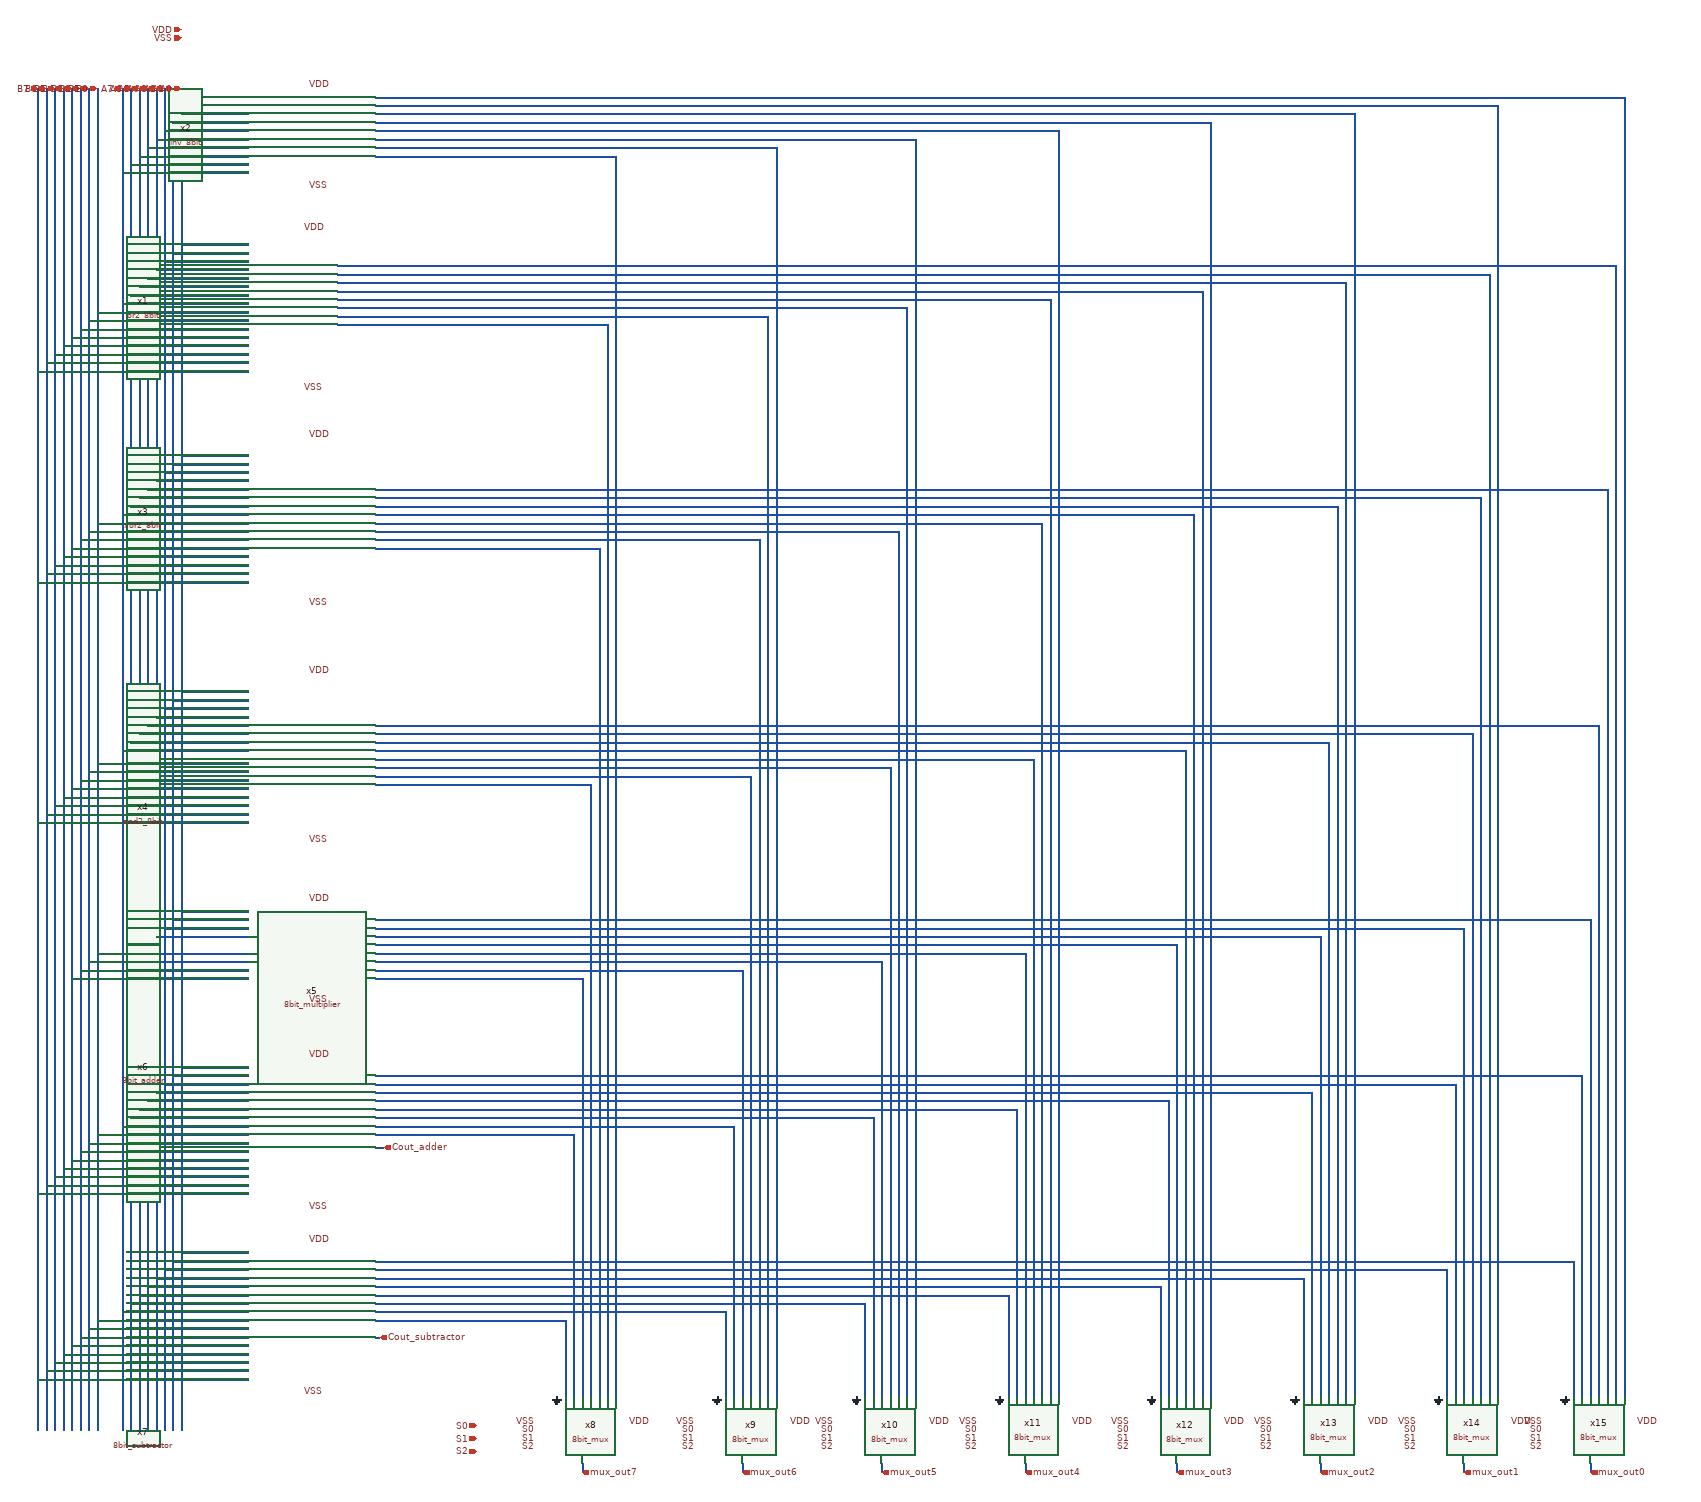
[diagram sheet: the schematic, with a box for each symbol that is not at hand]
v {xschem version=3.1.0 file_version=1.2 }
G {}
K {}
V {}
S {}
E {}
N -1880 -1640 -1880 1540 {
lab=A0}
N -1900 -1640 -1900 1540 {
lab=A1}
N -1920 -1640 -1920 1540 {
lab=A2}
N -1940 -1640 -1940 1540 {
lab=A3}
N -1960 -1640 -1960 1540 {
lab=A4}
N -1980 -1640 -1980 1540 {
lab=A5}
N -2000 -1640 -2000 1540 {
lab=A6}
N -2020 -1640 -2020 1540 {
lab=A7}
N -2080 -1640 -2080 1540 {
lab=B0}
N -2100 -1640 -2100 1540 {
lab=B1}
N -2120 -1640 -2120 1540 {
lab=B2}
N -2140 -1640 -2140 1540 {
lab=B3}
N -2160 -1640 -2160 1540 {
lab=B4}
N -2180 -1640 -2180 1540 {
lab=B5}
N -2200 -1640 -2200 1540 {
lab=B6}
N -2220 -1640 -2220 1540 {
lab=B7}
N -1880 -1580 -1720 -1580 {
lab=A0}
N -1900 -1560 -1720 -1560 {
lab=A1}
N -1920 -1540 -1720 -1540 {
lab=A2}
N -1940 -1520 -1720 -1520 {
lab=A3}
N -1960 -1500 -1720 -1500 {
lab=A4}
N -2000 -1460 -1720 -1460 {
lab=A6}
N -1980 -1480 -1720 -1480 {
lab=A5}
N -2020 -1440 -1720 -1440 {
lab=A7}
N -1880 -1270 -1720 -1270 {
lab=A0}
N -1900 -1250 -1720 -1250 {
lab=A1}
N -1920 -1230 -1720 -1230 {
lab=A2}
N -1940 -1210 -1720 -1210 {
lab=A3}
N -1960 -1190 -1720 -1190 {
lab=A4}
N -1980 -1170 -1720 -1170 {
lab=A5}
N -2000 -1150 -1720 -1150 {
lab=A6}
N -2020 -1130 -1720 -1130 {
lab=A7}
N -2080 -1110 -1720 -1110 {
lab=B0}
N -2100 -1090 -1720 -1090 {
lab=B1}
N -2120 -1070 -1720 -1070 {
lab=B2}
N -2140 -1050 -1720 -1050 {
lab=B3}
N -2160 -1030 -1720 -1030 {
lab=B4}
N -2180 -1010 -1720 -1010 {
lab=B5}
N -2200 -990 -1720 -990 {
lab=B6}
N -2220 -970 -1720 -970 {
lab=B7}
N -1880 -770 -1720 -770 {
lab=A0}
N -1900 -750 -1720 -750 {
lab=A1}
N -1920 -730 -1720 -730 {
lab=A2}
N -1940 -710 -1720 -710 {
lab=A3}
N -1960 -690 -1720 -690 {
lab=A4}
N -1980 -670 -1720 -670 {
lab=A5}
N -2000 -650 -1720 -650 {
lab=A6}
N -2020 -630 -1720 -630 {
lab=A7}
N -2080 -610 -1720 -610 {
lab=B0}
N -2100 -590 -1720 -590 {
lab=B1}
N -2120 -570 -1720 -570 {
lab=B2}
N -2140 -550 -1720 -550 {
lab=B3}
N -2160 -530 -1720 -530 {
lab=B4}
N -2180 -510 -1720 -510 {
lab=B5}
N -2200 -490 -1720 -490 {
lab=B6}
N -2220 -470 -1720 -470 {
lab=B7}
N -1880 -210 -1720 -210 {
lab=A0}
N -1900 -190 -1720 -190 {
lab=A1}
N -1920 -170 -1720 -170 {
lab=A2}
N -1940 -150 -1720 -150 {
lab=A3}
N -1950 -130 -1720 -130 {
lab=A4}
N -1960 -130 -1950 -130 {
lab=A4}
N -1980 -110 -1720 -110 {
lab=A5}
N -2000 -90 -1720 -90 {
lab=A6}
N -2020 -70 -1720 -70 {
lab=A7}
N -2080 -40 -1720 -40 {
lab=B0}
N -2100 -20 -1720 -20 {
lab=B1}
N -2120 0 -1720 0 {
lab=B2}
N -2140 20 -1720 20 {
lab=B3}
N -2160 40 -1720 40 {
lab=B4}
N -2180 60 -1720 60 {
lab=B5}
N -2200 80 -1720 80 {
lab=B6}
N -2220 100 -1720 100 {
lab=B7}
N -1880 310 -1720 310 {
lab=A0}
N -1900 330 -1720 330 {
lab=A1}
N -1920 350 -1720 350 {
lab=A2}
N -1940 370 -1720 370 {
lab=A3}
N -2080 410 -1720 410 {
lab=B0}
N -2100 430 -1720 430 {
lab=B1}
N -2120 450 -1720 450 {
lab=B2}
N -2140 470 -1720 470 {
lab=B3}
N -1880 680 -1720 680 {
lab=A0}
N -1900 700 -1720 700 {
lab=A1}
N -1920 720 -1720 720 {
lab=A2}
N -1940 740 -1720 740 {
lab=A3}
N -1960 760 -1720 760 {
lab=A4}
N -1980 780 -1720 780 {
lab=A5}
N -2000 800 -1720 800 {
lab=A6}
N -2020 820 -1720 820 {
lab=A7}
N -2080 840 -1720 840 {
lab=B0}
N -2100 860 -1720 860 {
lab=B1}
N -2120 880 -1720 880 {
lab=B2}
N -2140 900 -1720 900 {
lab=B3}
N -2160 920 -1720 920 {
lab=B4}
N -2180 940 -1720 940 {
lab=B5}
N -2200 960 -1720 960 {
lab=B6}
N -2220 980 -1720 980 {
lab=B7}
N -1880 1120 -1720 1120 {
lab=A0}
N -1900 1140 -1720 1140 {
lab=A1}
N -1920 1160 -1720 1160 {
lab=A2}
N -1940 1180 -1720 1180 {
lab=A3}
N -1960 1200 -1720 1200 {
lab=A4}
N -1980 1220 -1720 1220 {
lab=A5}
N -2000 1240 -1720 1240 {
lab=A6}
N -2020 1260 -1720 1260 {
lab=A7}
N -2080 1280 -1720 1280 {
lab=B0}
N -2100 1300 -1720 1300 {
lab=B1}
N -2120 1320 -1720 1320 {
lab=B2}
N -2140 1340 -1720 1340 {
lab=B3}
N -2160 1360 -1720 1360 {
lab=B4}
N -2180 1380 -1720 1380 {
lab=B5}
N -2200 1400 -1720 1400 {
lab=B6}
N -2220 1420 -1720 1420 {
lab=B7}
N -1420 -1480 -1140 -1480 {
lab=#net1}
N -1140 -1480 -1090 -1480 {
lab=#net1}
N -1090 -1480 -1040 -1480 {
lab=#net1}
N -850 -1470 -850 1470 {
lab=#net1}
N -1040 -1480 -970 -1480 {
lab=#net1}
N -470 -1470 -470 1470 {
lab=#net2}
N -140 -1470 -140 1470 {
lab=#net3}
N 200 -1480 200 1460 {
lab=#net4}
N 560 -1470 560 1470 {
lab=#net5}
N 900 -1480 900 1460 {
lab=#net6}
N 1240 -1480 1240 1460 {
lab=#net7}
N 1540 -1480 1540 1460 {
lab=#net8}
N -1420 -1500 -590 -1500 {
lab=#net2}
N -1420 -1520 -260 -1520 {
lab=#net3}
N -1420 -1540 80 -1540 {
lab=#net4}
N -1420 -1560 440 -1560 {
lab=#net5}
N -1420 -1580 780 -1580 {
lab=#net6}
N -1420 -1600 1120 -1600 {
lab=#net7}
N -1420 -1620 1420 -1620 {
lab=#net8}
N -970 -1480 -850 -1480 {
lab=#net1}
N -850 -1480 -850 -1470 {
lab=#net1}
N -590 -1500 -470 -1500 {
lab=#net2}
N -470 -1500 -470 -1470 {
lab=#net2}
N -260 -1520 -140 -1520 {
lab=#net3}
N -140 -1520 -140 -1470 {
lab=#net3}
N 80 -1540 200 -1540 {
lab=#net4}
N 200 -1540 200 -1480 {
lab=#net4}
N 440 -1560 560 -1560 {
lab=#net5}
N 560 -1560 560 -1470 {
lab=#net5}
N 780 -1580 900 -1580 {
lab=#net6}
N 900 -1580 900 -1480 {
lab=#net6}
N 1120 -1600 1240 -1600 {
lab=#net7}
N 1240 -1600 1240 -1480 {
lab=#net7}
N 1420 -1620 1540 -1620 {
lab=#net8}
N 1540 -1620 1540 -1480 {
lab=#net8}
N -870 -1080 -870 1460 {
lab=#net9}
N -1510 -1080 -870 -1080 {
lab=#net9}
N -490 -1080 -490 1460 {
lab=#net10}
N -160 -1080 -160 1460 {
lab=#net11}
N 180 -1080 180 1460 {
lab=#net12}
N 540 -1080 540 1460 {
lab=#net13}
N 880 -1080 880 1460 {
lab=#net14}
N 1220 -1080 1220 1460 {
lab=#net15}
N 1520 -1080 1520 1460 {
lab=#net16}
N -1510 -1100 -490 -1100 {
lab=#net10}
N -490 -1100 -490 -1080 {
lab=#net10}
N -1510 -1120 -160 -1120 {
lab=#net11}
N -160 -1120 -160 -1080 {
lab=#net11}
N -1510 -1140 180 -1140 {
lab=#net12}
N 180 -1140 180 -1080 {
lab=#net12}
N -1510 -1160 540 -1160 {
lab=#net13}
N 540 -1160 540 -1080 {
lab=#net13}
N -1510 -1180 880 -1180 {
lab=#net14}
N 880 -1180 880 -1080 {
lab=#net14}
N -1510 -1200 1220 -1200 {
lab=#net15}
N 1220 -1200 1220 -1080 {
lab=#net15}
N -1510 -1220 1520 -1220 {
lab=#net16}
N 1520 -1220 1520 -1080 {
lab=#net16}
N -890 -550 -890 1460 {
lab=#net17}
N -1420 -550 -890 -550 {
lab=#net17}
N -510 -550 -510 1460 {
lab=#net18}
N -180 -550 -180 1460 {
lab=#net19}
N 160 -550 160 1460 {
lab=#net20}
N 520 -550 520 1460 {
lab=#net21}
N 860 -550 860 1460 {
lab=#net22}
N 1200 -550 1200 1460 {
lab=#net23}
N 1500 -550 1500 1460 {
lab=#net24}
N -1420 -570 -510 -570 {
lab=#net18}
N -510 -570 -510 -550 {
lab=#net18}
N -1420 -590 -180 -590 {
lab=#net19}
N -180 -590 -180 -550 {
lab=#net19}
N -1420 -610 160 -610 {
lab=#net20}
N 160 -610 160 -550 {
lab=#net20}
N -1420 -630 520 -630 {
lab=#net21}
N 520 -630 520 -550 {
lab=#net21}
N -1420 -650 860 -650 {
lab=#net22}
N 860 -650 860 -550 {
lab=#net22}
N -1420 -670 1200 -670 {
lab=#net23}
N 1200 -670 1200 -550 {
lab=#net23}
N -1420 -690 1490 -690 {
lab=#net24}
N 1490 -690 1500 -690 {
lab=#net24}
N 1500 -690 1500 -550 {
lab=#net24}
N -910 10 -910 1460 {
lab=#net25}
N -1420 10 -910 10 {
lab=#net25}
N -530 10 -530 1460 {
lab=#net26}
N -200 10 -200 1460 {
lab=#net27}
N 140 10 140 1460 {
lab=#net28}
N 500 10 500 1460 {
lab=#net29}
N 840 10 840 1460 {
lab=#net30}
N 1180 10 1180 1460 {
lab=#net31}
N 1480 10 1480 1460 {
lab=#net32}
N -1420 -10 -530 -10 {
lab=#net26}
N -530 -10 -530 10 {
lab=#net26}
N -1420 -30 -200 -30 {
lab=#net27}
N -200 -30 -200 10 {
lab=#net27}
N -1420 -50 140 -50 {
lab=#net28}
N 140 -50 140 10 {
lab=#net28}
N -1420 -70 500 -70 {
lab=#net29}
N 500 -70 500 10 {
lab=#net29}
N -1420 -90 840 -90 {
lab=#net30}
N 840 -90 840 10 {
lab=#net30}
N -1420 -110 1180 -110 {
lab=#net31}
N 1180 -110 1180 10 {
lab=#net31}
N -1420 -130 1480 -130 {
lab=#net32}
N 1480 -130 1480 10 {
lab=#net32}
N -930 470 -930 1460 {
lab=#net33}
N -1420 470 -930 470 {
lab=#net33}
N -550 470 -550 1460 {
lab=#net34}
N -220 470 -220 1460 {
lab=#net35}
N 120 470 120 1460 {
lab=#net36}
N 480 470 480 1460 {
lab=#net37}
N 820 470 820 1460 {
lab=#net38}
N 1160 470 1160 1460 {
lab=#net39}
N 1460 470 1460 1460 {
lab=#net40}
N -1420 450 -550 450 {
lab=#net34}
N -550 450 -550 470 {
lab=#net34}
N -1420 430 -220 430 {
lab=#net35}
N -220 430 -220 470 {
lab=#net35}
N -1420 410 120 410 {
lab=#net36}
N 120 410 120 470 {
lab=#net36}
N -1420 390 480 390 {
lab=#net37}
N 480 390 480 470 {
lab=#net37}
N -1420 370 820 370 {
lab=#net38}
N 820 370 820 470 {
lab=#net38}
N -1420 350 1160 350 {
lab=#net39}
N 1160 350 1160 470 {
lab=#net39}
N -1420 330 1460 330 {
lab=#net40}
N 1460 330 1460 470 {
lab=#net40}
N -950 840 -950 1460 {
lab=#net41}
N -1420 840 -950 840 {
lab=#net41}
N -1420 820 -570 820 {
lab=#net42}
N -570 820 -570 1460 {
lab=#net42}
N -1420 800 -240 800 {
lab=#net43}
N -240 800 -240 1460 {
lab=#net43}
N -1420 780 100 780 {
lab=#net44}
N 100 780 100 1460 {
lab=#net44}
N -1420 760 460 760 {
lab=#net45}
N 460 760 460 1460 {
lab=#net45}
N -1420 740 800 740 {
lab=#net46}
N 800 740 800 1460 {
lab=#net46}
N -1420 720 1140 720 {
lab=#net47}
N 1140 720 1140 1460 {
lab=#net47}
N -1420 700 1440 700 {
lab=#net48}
N 1440 700 1440 1460 {
lab=#net48}
N -1420 1280 -970 1280 {
lab=#net49}
N -970 1280 -970 1460 {
lab=#net49}
N -1420 1260 -590 1260 {
lab=#net50}
N -590 1260 -590 1460 {
lab=#net50}
N -1420 1240 -260 1240 {
lab=#net51}
N -260 1240 -260 1460 {
lab=#net51}
N 780 1200 780 1460 {
lab=#net52}
N 1120 1180 1120 1460 {
lab=#net53}
N 1420 1160 1420 1460 {
lab=#net54}
N -1420 1220 80 1220 {
lab=#net55}
N 80 1220 80 1460 {
lab=#net55}
N -1420 1200 440 1200 {
lab=#net56}
N 440 1200 440 1460 {
lab=#net56}
N -1420 1180 780 1180 {
lab=#net52}
N 780 1180 780 1200 {
lab=#net52}
N -1420 1160 1120 1160 {
lab=#net53}
N 1120 1160 1120 1180 {
lab=#net53}
N -1420 1140 1420 1140 {
lab=#net54}
N 1420 1140 1420 1160 {
lab=#net54}
N -1420 1320 -1410 1320 {
lab=Cout_subtractor}
N -1420 870 -1400 870 {
lab=Cout_adder}
N -930 1620 -930 1640 {
lab=mux_out7}
N -550 1620 -550 1640 {
lab=mux_out6}
N -220 1620 -220 1640 {
lab=mux_out5}
N 120 1620 120 1640 {
lab=mux_out4}
N 480 1620 480 1640 {
lab=mux_out3}
N 820 1620 820 1640 {
lab=mux_out2}
N 1160 1620 1160 1640 {
lab=mux_out1}
N 1460 1620 1460 1640 {
lab=mux_out0}
C {or/or2_8bit.sym} -1570 -1140 0 0 {name=x1}
C {inv/inv_8bit.sym} -1570 -1530 0 0 {name=x2}
C {xor2/xor2_8bit.sym} -1570 -620 0 0 {name=x3}
C {and/and2_8bit.sym} -1570 -60 0 0 {name=x4}
C {8bit_multiplier.sym} -1320 540 0 0 {name=x5}
C {8bit_adder.sym} -1570 830 0 0 {name=x6}
C {8bit_subtractor.sym} -1570 1270 0 0 {name=x7}
C {devices/ipin.sym} -1900 -1640 1 0 {name=p2 lab=A1}
C {devices/ipin.sym} -1920 -1640 1 0 {name=p3 lab=A2}
C {devices/ipin.sym} -1940 -1640 1 0 {name=p4 lab=A3}
C {devices/ipin.sym} -1960 -1640 1 0 {name=p5 lab=A4}
C {devices/ipin.sym} -1980 -1640 1 0 {name=p6 lab=A5}
C {devices/ipin.sym} -2000 -1640 1 0 {name=p7 lab=A6}
C {devices/ipin.sym} -2020 -1640 1 0 {name=p8 lab=A7}
C {devices/ipin.sym} -1880 -1640 1 0 {name=p9 lab=A0}
C {devices/ipin.sym} -2100 -1640 1 0 {name=p11 lab=B1}
C {devices/ipin.sym} -2120 -1640 1 0 {name=p12 lab=B2}
C {devices/ipin.sym} -2140 -1640 1 0 {name=p13 lab=B3}
C {devices/ipin.sym} -2160 -1640 1 0 {name=p14 lab=B4}
C {devices/ipin.sym} -2180 -1640 1 0 {name=p15 lab=B5}
C {devices/ipin.sym} -2200 -1640 1 0 {name=p16 lab=B6}
C {devices/ipin.sym} -2220 -1640 1 0 {name=p17 lab=B7}
C {devices/ipin.sym} -2080 -1640 1 0 {name=p18 lab=B0}
C {devices/ipin.sym} -1880 -1780 0 0 {name=p1 lab=VDD}
C {devices/ipin.sym} -1880 -1760 0 0 {name=p10 lab=VSS}
C {devices/lab_pin.sym} -1580 -1650 2 0 {name=l1 sig_type=std_logic lab=VDD}
C {devices/lab_pin.sym} -1580 -1410 2 0 {name=l2 sig_type=std_logic lab=VSS}
C {8bit_mux.sym} -940 1600 1 0 {name=x8}
C {8bit_mux.sym} -560 1600 1 0 {name=x9}
C {8bit_mux.sym} -230 1600 1 0 {name=x10}
C {8bit_mux.sym} 110 1600 1 0 {name=x11}
C {8bit_mux.sym} 470 1600 1 0 {name=x12}
C {8bit_mux.sym} 810 1600 1 0 {name=x13}
C {8bit_mux.sym} 1150 1600 1 0 {name=x14}
C {8bit_mux.sym} 1450 1600 1 0 {name=x15}
C {devices/lab_pin.sym} -1590 -1310 2 0 {name=l4 sig_type=std_logic lab=VDD}
C {devices/lab_pin.sym} -1580 -820 2 0 {name=l5 sig_type=std_logic lab=VDD}
C {devices/lab_pin.sym} -1580 -260 2 0 {name=l6 sig_type=std_logic lab=VDD}
C {devices/lab_pin.sym} -1580 280 2 0 {name=l7 sig_type=std_logic lab=VDD}
C {devices/lab_pin.sym} -1580 650 2 0 {name=l8 sig_type=std_logic lab=VDD}
C {devices/lab_pin.sym} -1580 1090 2 0 {name=l9 sig_type=std_logic lab=VDD}
C {devices/lab_pin.sym} -820 1520 2 0 {name=l10 sig_type=std_logic lab=VDD}
C {devices/lab_pin.sym} -440 1520 2 0 {name=l11 sig_type=std_logic lab=VDD}
C {devices/lab_pin.sym} -110 1520 2 0 {name=l12 sig_type=std_logic lab=VDD}
C {devices/lab_pin.sym} 230 1520 2 0 {name=l13 sig_type=std_logic lab=VDD}
C {devices/lab_pin.sym} 590 1520 2 0 {name=l14 sig_type=std_logic lab=VDD}
C {devices/lab_pin.sym} 930 1520 2 0 {name=l15 sig_type=std_logic lab=VDD}
C {devices/lab_pin.sym} 1270 1520 2 0 {name=l16 sig_type=std_logic lab=VDD}
C {devices/lab_pin.sym} 1570 1520 2 0 {name=l17 sig_type=std_logic lab=VDD}
C {devices/lab_pin.sym} -1590 -930 2 0 {name=l3 sig_type=std_logic lab=VSS}
C {devices/lab_pin.sym} -1580 -420 2 0 {name=l18 sig_type=std_logic lab=VSS}
C {devices/lab_pin.sym} -1580 140 2 0 {name=l19 sig_type=std_logic lab=VSS}
C {devices/lab_pin.sym} -1580 520 2 0 {name=l20 sig_type=std_logic lab=VSS}
C {devices/lab_pin.sym} -1580 1010 2 0 {name=l21 sig_type=std_logic lab=VSS}
C {devices/lab_pin.sym} -1590 1450 2 0 {name=l22 sig_type=std_logic lab=VSS}
C {devices/lab_pin.sym} -1040 1520 0 0 {name=l23 sig_type=std_logic lab=VSS}
C {devices/lab_pin.sym} -660 1520 0 0 {name=l24 sig_type=std_logic lab=VSS}
C {devices/lab_pin.sym} -330 1520 0 0 {name=l25 sig_type=std_logic lab=VSS}
C {devices/lab_pin.sym} 10 1520 0 0 {name=l26 sig_type=std_logic lab=VSS}
C {devices/lab_pin.sym} 370 1520 0 0 {name=l27 sig_type=std_logic lab=VSS}
C {devices/lab_pin.sym} 710 1520 0 0 {name=l28 sig_type=std_logic lab=VSS}
C {devices/lab_pin.sym} 1050 1520 0 0 {name=l29 sig_type=std_logic lab=VSS}
C {devices/lab_pin.sym} 1350 1520 0 0 {name=l30 sig_type=std_logic lab=VSS}
C {devices/ipin.sym} -1180 1530 0 0 {name=p19 lab=S0}
C {devices/ipin.sym} -1180 1560 0 0 {name=p20 lab=S1}
C {devices/ipin.sym} -1180 1590 0 0 {name=p21 lab=S2}
C {devices/lab_pin.sym} -1040 1540 0 0 {name=l31 sig_type=std_logic lab=S0}
C {devices/lab_pin.sym} -1040 1560 0 0 {name=l32 sig_type=std_logic lab=S1}
C {devices/lab_pin.sym} -1040 1580 0 0 {name=l33 sig_type=std_logic lab=S2}
C {devices/lab_pin.sym} -660 1540 0 0 {name=l34 sig_type=std_logic lab=S0}
C {devices/lab_pin.sym} -330 1540 0 0 {name=l35 sig_type=std_logic lab=S0}
C {devices/lab_pin.sym} 10 1540 0 0 {name=l36 sig_type=std_logic lab=S0}
C {devices/lab_pin.sym} 370 1540 0 0 {name=l37 sig_type=std_logic lab=S0}
C {devices/lab_pin.sym} 710 1540 0 0 {name=l38 sig_type=std_logic lab=S0}
C {devices/lab_pin.sym} 1050 1540 0 0 {name=l39 sig_type=std_logic lab=S0}
C {devices/lab_pin.sym} 1350 1540 0 0 {name=l40 sig_type=std_logic lab=S0}
C {devices/lab_pin.sym} -660 1560 0 0 {name=l41 sig_type=std_logic lab=S1}
C {devices/lab_pin.sym} -330 1560 0 0 {name=l42 sig_type=std_logic lab=S1}
C {devices/lab_pin.sym} 10 1560 0 0 {name=l43 sig_type=std_logic lab=S1}
C {devices/lab_pin.sym} 370 1560 0 0 {name=l44 sig_type=std_logic lab=S1}
C {devices/lab_pin.sym} 710 1560 0 0 {name=l45 sig_type=std_logic lab=S1}
C {devices/lab_pin.sym} 1050 1560 0 0 {name=l46 sig_type=std_logic lab=S1}
C {devices/lab_pin.sym} 1350 1560 0 0 {name=l47 sig_type=std_logic lab=S1}
C {devices/lab_pin.sym} -660 1580 0 0 {name=l48 sig_type=std_logic lab=S2}
C {devices/lab_pin.sym} -330 1580 0 0 {name=l49 sig_type=std_logic lab=S2}
C {devices/lab_pin.sym} 10 1580 0 0 {name=l50 sig_type=std_logic lab=S2}
C {devices/lab_pin.sym} 370 1580 0 0 {name=l51 sig_type=std_logic lab=S2}
C {devices/lab_pin.sym} 710 1580 0 0 {name=l52 sig_type=std_logic lab=S2}
C {devices/lab_pin.sym} 1050 1580 0 0 {name=l53 sig_type=std_logic lab=S2}
C {devices/lab_pin.sym} 1350 1580 0 0 {name=l54 sig_type=std_logic lab=S2}
C {devices/gnd.sym} -990 1460 2 0 {name=l55 lab=GND}
C {devices/gnd.sym} -610 1460 2 0 {name=l56 lab=GND}
C {devices/gnd.sym} -280 1460 2 0 {name=l57 lab=GND}
C {devices/gnd.sym} 60 1460 2 0 {name=l58 lab=GND}
C {devices/opin.sym} -1400 870 0 0 {name=p22 lab=Cout_adder}
C {devices/opin.sym} -1410 1320 0 0 {name=p23 lab=Cout_subtractor}
C {devices/opin.sym} 1460 1640 1 0 {name=p24 lab=mux_out0}
C {devices/opin.sym} 1160 1640 1 0 {name=p25 lab=mux_out1}
C {devices/opin.sym} 820 1640 1 0 {name=p26 lab=mux_out2}
C {devices/opin.sym} 480 1640 1 0 {name=p27 lab=mux_out3}
C {devices/opin.sym} 120 1640 1 0 {name=p28 lab=mux_out4}
C {devices/opin.sym} -220 1640 1 0 {name=p29 lab=mux_out5}
C {devices/opin.sym} -550 1640 1 0 {name=p30 lab=mux_out6}
C {devices/opin.sym} -930 1640 1 0 {name=p31 lab=mux_out7}
C {devices/gnd.sym} 420 1460 2 0 {name=l59 lab=GND}
C {devices/gnd.sym} 760 1460 2 0 {name=l60 lab=GND}
C {devices/gnd.sym} 1100 1460 2 0 {name=l61 lab=GND}
C {devices/gnd.sym} 1400 1460 2 0 {name=l62 lab=GND}
